One B-rep face of a CAD part: STEP entity #4174.
In plain terms, the planar face has unit normal (-1, 0, 0).
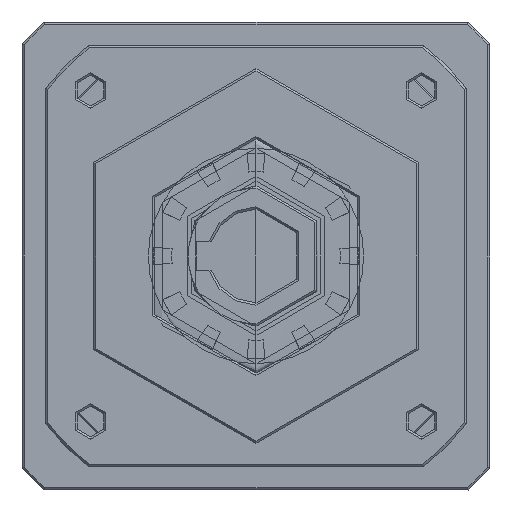
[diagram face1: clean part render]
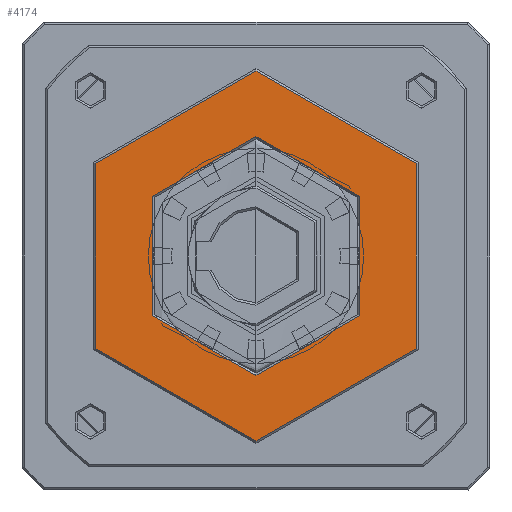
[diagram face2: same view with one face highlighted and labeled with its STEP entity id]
Its self-contained STEP definition (entity closure, numbers rounded to 3 decimals):
#2062 = EDGE_CURVE ( 'NONE', #75123, #43518, #20827, .T. ) ;
#4174 = ADVANCED_FACE ( 'NONE', ( #20408, #24783 ), #26033, .F. ) ;
#6217 = DIRECTION ( 'NONE',  ( 0., 0., -1. ) ) ;
#7553 = EDGE_CURVE ( 'NONE', #44633, #59437, #81831, .T. ) ;
#8306 = CIRCLE ( 'NONE', #70564, 39.5 ) ;
#15024 = AXIS2_PLACEMENT_3D ( 'NONE', #18482, #46586, #39915 ) ;
#18409 = EDGE_LOOP ( 'NONE', ( #74258, #23186 ) ) ;
#18482 = CARTESIAN_POINT ( 'NONE',  ( 0., 0., 0. ) ) ;
#20408 = FACE_BOUND ( 'NONE', #31753, .T. ) ;
#20418 = CARTESIAN_POINT ( 'NONE',  ( 0., 0., 0. ) ) ;
#20827 = CIRCLE ( 'NONE', #15024, 39.5 ) ;
#23174 = CARTESIAN_POINT ( 'NONE',  ( 0., 0., -39.5 ) ) ;
#23186 = ORIENTED_EDGE ( 'NONE', *, *, #77967, .T. ) ;
#24783 = FACE_OUTER_BOUND ( 'NONE', #18409, .T. ) ;
#26033 = PLANE ( 'NONE',  #82297 ) ;
#26928 = CARTESIAN_POINT ( 'NONE',  ( 0., 0., 0. ) ) ;
#31446 = AXIS2_PLACEMENT_3D ( 'NONE', #87771, #39444, #67226 ) ;
#31753 = EDGE_LOOP ( 'NONE', ( #49580, #74811 ) ) ;
#39444 = DIRECTION ( 'NONE',  ( -1., 0., 0. ) ) ;
#39915 = DIRECTION ( 'NONE',  ( 0., 0., -1. ) ) ;
#41356 = CIRCLE ( 'NONE', #48894, 25.5 ) ;
#43518 = VERTEX_POINT ( 'NONE', #57746 ) ;
#44633 = VERTEX_POINT ( 'NONE', #56498 ) ;
#46586 = DIRECTION ( 'NONE',  ( -1., 0., 0. ) ) ;
#47625 = DIRECTION ( 'NONE',  ( -1., 0., 0. ) ) ;
#48381 = CARTESIAN_POINT ( 'NONE',  ( 0., 0., -25.5 ) ) ;
#48894 = AXIS2_PLACEMENT_3D ( 'NONE', #26928, #62259, #75557 ) ;
#49580 = ORIENTED_EDGE ( 'NONE', *, *, #7553, .F. ) ;
#53035 = EDGE_CURVE ( 'NONE', #59437, #44633, #41356, .T. ) ;
#56498 = CARTESIAN_POINT ( 'NONE',  ( 0., 0., 25.5 ) ) ;
#57746 = CARTESIAN_POINT ( 'NONE',  ( 0., 0., 39.5 ) ) ;
#59437 = VERTEX_POINT ( 'NONE', #48381 ) ;
#60178 = CARTESIAN_POINT ( 'NONE',  ( 0., -39.974, 39.974 ) ) ;
#62259 = DIRECTION ( 'NONE',  ( -1., 0., 0. ) ) ;
#67226 = DIRECTION ( 'NONE',  ( 0., 0., 1. ) ) ;
#70564 = AXIS2_PLACEMENT_3D ( 'NONE', #20418, #47625, #6217 ) ;
#74081 = DIRECTION ( 'NONE',  ( 1., 0., 0. ) ) ;
#74258 = ORIENTED_EDGE ( 'NONE', *, *, #2062, .T. ) ;
#74368 = DIRECTION ( 'NONE',  ( 0., 0., -1. ) ) ;
#74811 = ORIENTED_EDGE ( 'NONE', *, *, #53035, .F. ) ;
#75123 = VERTEX_POINT ( 'NONE', #23174 ) ;
#75557 = DIRECTION ( 'NONE',  ( 0., 0., 1. ) ) ;
#77967 = EDGE_CURVE ( 'NONE', #43518, #75123, #8306, .T. ) ;
#81831 = CIRCLE ( 'NONE', #31446, 25.5 ) ;
#82297 = AXIS2_PLACEMENT_3D ( 'NONE', #60178, #74081, #74368 ) ;
#87771 = CARTESIAN_POINT ( 'NONE',  ( 0., 0., 0. ) ) ;
